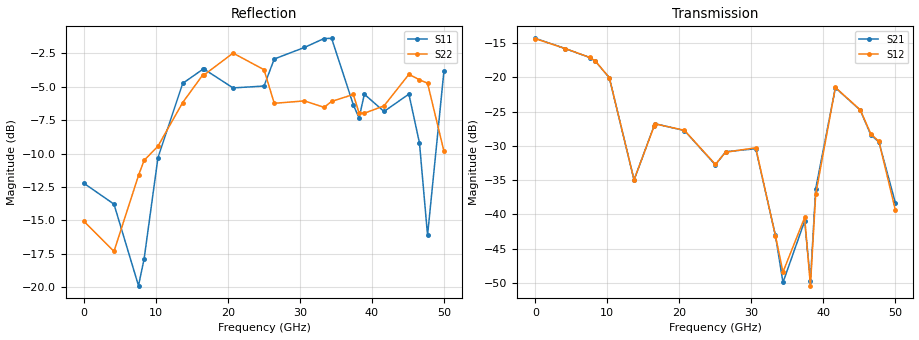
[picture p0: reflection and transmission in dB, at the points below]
!Keysight Technologies,N5245B,MY58422270,A.16.20.02
!Date: Thursday, March 05, 2026 01:05:34
!Correction: S11(C  2-Port  )
!S21(C  2-Port  )
!S12(C  2-Port  )
!S22(C  2-Port  )
!S2P File: Measurements: S11, S21, S12, S22:
# Hz S  dB  R 50
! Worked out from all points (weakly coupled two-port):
!   3201 points, 10 MHz to 50 GHz, reference 50 ohm
!   highest |S21| = -14.31 dB at 10 MHz (marker M1); lowest = -50.0 dB at 34.39 GHz (marker M2)
!   lowest |S11| = -19.9 dB at 7.571 GHz (marker M3), VSWR 1.23, Z = 40.9 - j1.24 ohm
!   |S11| at or under -10 dB: start of sweep to 10.39 GHz; 46.72 GHz to 48.26 GHz (1.536 GHz wide, 3.23 % of centre)
!   |S22| runs from -19.0 to -2.5 dB; largest |S21 - S12| = 0.0067
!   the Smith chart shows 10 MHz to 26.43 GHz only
!   S11 on the Smith chart (normalised r, x): 10 MHz: 1.64, -0.06; 10.27 GHz: 0.54, +0.12; 13.71 GHz: 1.03, +1.44; 16.51 GHz: 1.51, -2.05; 20.71 GHz: 0.34, -0.43; 26.43 GHz: 0.18, +0.27
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1e7  -12.23 -3.8  -14.31 3.4  -14.36 1.9  -15.07 39.5
4.165419e9  -13.78 -132.1  -15.81 -171.2  -15.80 -171.3  -17.31 -115.7
7.570988e9  -19.87 -171.5  -17.11 41.7  -17.10 41.8  -11.64 -155.8
8.352081e9  -17.86 -161.6  -17.66 6.7  -17.64 6.8  -10.51 -174.2
1.027357e10  -10.31 161.1  -20.06 -78.4  -20.04 -78.5  -9.45 123.7
1.371038e10  -4.76 53.4  -34.99 -178.0  -34.97 -178.5  -6.19 -48.6
1.65067e10  -3.71 -36.8  -27.05 163.8  -27.11 164.0  -4.12 -140.6
1.667854e10  -3.70 -41.8  -26.79 157.7  -26.81 157.7  -4.13 -144.2
2.070898e10  -5.10 -129.0  -27.77 31.1  -27.74 31.2  -2.50 145.4
2.5005e10  -4.96 174.6  -32.79 -66.6  -32.71 -65.9  -3.74 70.5
2.642659e10  -2.94 149.3  -30.86 -94.2  -30.94 -94.3  -6.25 40.0
3.061325e10  -2.08 79.4  -30.43 123.2  -30.29 123.0  -6.07 -53.1
3.334708e10  -1.41 35.7  -43.10 -0.9  -43.15 -0.5  -6.55 -132.8
3.439375e10  -1.40 17.4  -49.96 -106.0  -48.44 -111.4  -6.11 -156.0
3.740877e10  -6.36 -41.9  -40.97 73.8  -40.47 71.5  -5.59 146.1
3.820548e10  -7.35 -22.0  -49.77 67.8  -50.43 -72.3  -6.98 133.9
3.893971e10  -5.57 -30.0  -36.27 98.4  -37.08 98.4  -6.99 136.9
4.167354e10  -6.86 -55.1  -21.52 -56.9  -21.48 -57.2  -6.44 110.3
4.512598e10  -5.56 -101.8  -24.79 86.6  -24.75 86.0  -4.09 74.0
4.659443e10  -9.21 -153.4  -28.40 32.2  -28.26 33.1  -4.49 53.8
4.771921e10  -16.11 69.0  -29.45 -13.4  -29.36 -12.7  -4.75 41.6
5e10  -3.81 -72.3  -38.32 -110.9  -39.37 -110.6  -9.84 9.1
